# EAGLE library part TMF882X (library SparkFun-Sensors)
AMS TMF882x Direct Time of Flight Sensor The TMF8820/21 is a direct time-of-flight (dToF) sensor in a single modular package with associated VCSEL. The dToF device is based on SPAD, TDC and histogram technology and achieves 5000 mm detection range. Due to its lens on the SPAD, it supports 3x3, 4x4, and 3x6 multizone output data and a very wide, dynamically adjustable, field of view. A multi-lens-array (MLA) inside the package above the VCSEL widens up the FoI (field of illumination). All processing of the raw data is performed on-chip and the TMF8820/21 provide distance information together with confidence values on its I2C interface. Datasheet Hookup Guide

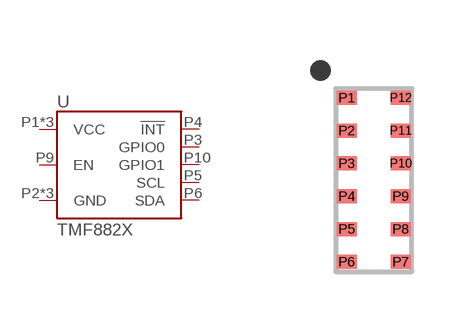
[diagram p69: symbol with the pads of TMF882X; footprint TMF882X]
Designator prefix U

## TMF882X_TMF8820 (PROD_ID: IC-16432)  [TMF882X]
P1  VCC  pwr
P2  GND  pwr
P3  GPIO0
P4  !INT!
P5  SCL
P6  SDA
P7  VCC  pwr
P8  GND  pwr
P9  EN  in
P10  GPIO1
P11  GND  pwr
P12  VCC  pwr

## TMF882X_TMF8821 (PROD_ID: IC-16433)  [TMF882X]
Pads as for TMF882X

## Footprint TMF882X (pad centres in mm)
OLGA12 Mechanical Specifications: Pad Size:.5mm x .3mm Pin count: 12 Pin pitch: .82mm Package Size: 1.4mm x 2mm Datasheet
smd 0.5 x 0.35: P1 -0.686,2.032; P2 -0.686,1.212; P3 -0.686,0.392; P4 -0.686,-0.428; P5 -0.686,-1.248; P6 -0.686,-2.068; P7 0.664,-2.068; P8 0.664,-1.248; P9 0.664,-0.428; P10 0.664,0.392; P11 0.664,1.212; P12 0.664,2.032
